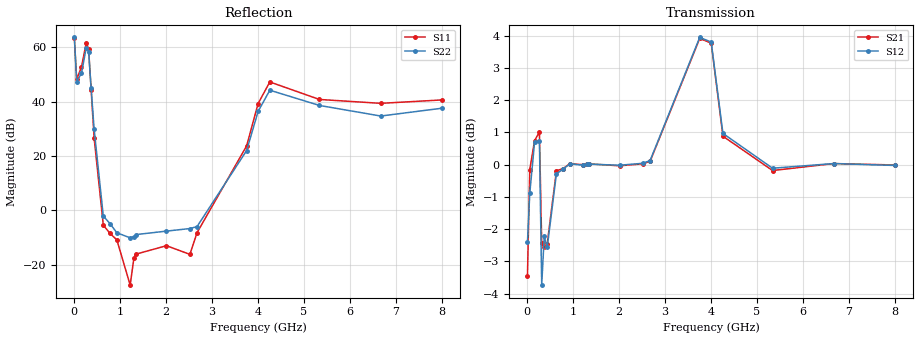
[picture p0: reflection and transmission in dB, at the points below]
!Agilent Technologies,N5230A,US43500312,A.07.50.67
!Agilent N5230A: A.07.50.67
!Date: Tuesday, June 09, 2015 15:35:30
!Correction: S11(Full 2 Port(1,2))
!S21(Full 2 Port(1,2))
!S12(Full 2 Port(1,2))
!S22(Full 2 Port(1,2))
!S2P File: Measurements: S11, S21, S12, S22:
# Hz S  MA  R 50
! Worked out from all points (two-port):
!   1601 points, 10 MHz to 8 GHz, reference 50 ohm
!   highest |S21| = 3.91 dB at 3.755 GHz (marker M1); lowest = -3.4 dB at 10 MHz (marker M2)
!   |S21| within 3 dB of the highest: 231.3 MHz to 245 MHz (13.75 MHz wide, 5.77 % of centre); 3.476 GHz to 4.253 GHz (777.1 MHz wide, 20.1 % of centre) (the widest 2 of 13)
!   lowest |S11| = -27.6 dB at 1.223 GHz (marker M3), VSWR 1.09, Z = 52.4 + j3.52 ohm
!   |S11| at or under -10 dB: 798.9 MHz to 956.9 MHz (158 MHz wide, 18 % of centre); 1.046 GHz to 2.093 GHz (1.047 GHz wide, 66.7 % of centre); 2.404 GHz to 2.647 GHz (243.4 MHz wide, 9.64 % of centre) (the widest 3 of 4)
!   |S22| runs from -14.0 to 63.6 dB; largest |S21 - S12| = 0.49
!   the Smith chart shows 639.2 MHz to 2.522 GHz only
!   S11 on the Smith chart (normalised r, x): 639.2 MHz: 0.39, +0.50; 784 MHz: 0.46, +0.11; 933.8 MHz: 1.01, -0.60; 1.303 GHz: 0.86, +0.20; 2.012 GHz: 0.64, +0.07; 2.522 GHz: 0.77, -0.14
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1e7  1499 171.2  0.673 -40.8  0.7599 -12.7  1520 -19.4
5.99375e7  257.2 326.1  0.9824 -1.9  0.9025 -6.3  231.9 92.3
1.648062e8  432.9 401.7  1.09 8.1  1.084 6.5  334.1 123.8
2.69675e8  1223 384.3  1.123 -11.6  1.087 -6.9  988 101.6
3.196125e8  932.2 423.0  0.7548 17.4  0.6506 7.1  833.4 147.3
3.745438e8  164.4 436.6  0.7452 8.6  0.7742 2.9  176.3 177.8
4.394625e8  21.51 420.0  0.7545 8.1  0.7441 8.1  31.04 198.3
6.392125e8  0.5309 480.6  0.9786 16.5  0.9677 16.6  0.7812 378.2
7.840312e8  0.3747 523.6  0.986 12.8  0.9842 12.6  0.5683 458.3
9.338438e8  0.2844 647.4  1.004 12.3  1.003 12.3  0.3834 579.9
1.223481e9  0.04179 773.3  0.9996 13.0  0.9983 13.2  0.3109 698.5
1.303381e9  0.1295 837.7  1.002 13.0  1.002 13.1  0.3265 747.4
1.343331e9  0.1549 844.5  1.003 12.9  1.002 13.0  0.3555 764.9
2.012494e9  0.2223 885.7  0.996 12.2  0.998 12.3  0.4125 1042.7
2.521856e9  0.1539 936.0  1.003 13.6  1.005 13.6  0.4599 1162.1
2.676662e9  0.3851 1025.9  1.012 13.8  1.015 13.8  0.4992 1229.3
3.755312e9  15.27 1397.4  1.569 15.8  1.575 15.9  12.53 1530.4
4.005e9  92.04 1397.1  1.543 0.3  1.549 0.4  65.97 1522.1
4.259681e9  229.8 1344.0  1.107 -15.5  1.118 -15.1  161.9 1459.1
5.338331e9  109.4 1322.0  0.9793 1.7  0.9874 2.1  84.88 1401.1
6.671662e9  92.83 1359.0  1.004 1.8  1.004 2.4  54.19 1340.3
8e9  107.2 1387.0  0.9989 2.0  0.9972 1.9  75.43 1308.1
